VERSION 5.7 ;
  DIVIDERCHAR "/" ;
  BUSBITCHARS "[]" ;
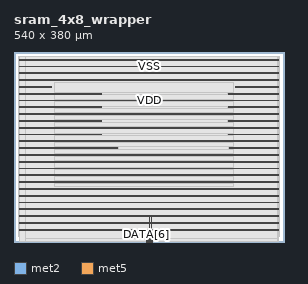
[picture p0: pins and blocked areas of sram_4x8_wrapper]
MACRO sram_4x8_wrapper
  CLASS BLOCK ;
  FOREIGN sram_4x8_wrapper ;
  ORIGIN 0.000 0.000 ;
  SIZE 540.000 BY 380.000 ;
  PIN ADDR[0]
    ANTENNAGATEAREA 0.126000 ;
    DIRECTION INPUT ;
    USE SIGNAL ;
    PORT
      LAYER met2 ;
        RECT 276.160 0.000 276.300 17.040 ;
    END
  END ADDR[0]
  PIN ADDR[1]
    ANTENNAGATEAREA 0.126000 ;
    DIRECTION INPUT ;
    USE SIGNAL ;
    PORT
      LAYER met2 ;
        RECT 269.720 0.000 269.860 16.700 ;
    END
  END ADDR[1]
  PIN CLK
    ANTENNAGATEAREA 0.213000 ;
    DIRECTION INPUT ;
    USE CLOCK ;
    PORT
      LAYER met2 ;
        RECT 273.400 0.000 273.540 6.320 ;
    END
  END CLK
  PIN CSb
    ANTENNAGATEAREA 0.495000 ;
    DIRECTION INPUT ;
    USE SIGNAL ;
    PORT
      LAYER met2 ;
        RECT 270.640 0.000 270.780 9.250 ;
    END
  END CSb
  PIN DATA[0]
    ANTENNAGATEAREA 0.126000 ;
    ANTENNADIFFAREA 0.601000 ;
    DIRECTION INOUT ;
    USE SIGNAL ;
    PORT
      LAYER met2 ;
        RECT 267.880 0.000 268.020 10.240 ;
    END
  END DATA[0]
  PIN DATA[1]
    ANTENNAGATEAREA 0.126000 ;
    ANTENNADIFFAREA 0.601000 ;
    DIRECTION INOUT ;
    USE SIGNAL ;
    PORT
      LAYER met2 ;
        RECT 266.960 0.000 267.100 9.930 ;
    END
  END DATA[1]
  PIN DATA[2]
    ANTENNAGATEAREA 0.126000 ;
    ANTENNADIFFAREA 0.601000 ;
    DIRECTION INOUT ;
    USE SIGNAL ;
    PORT
      LAYER met2 ;
        RECT 275.240 0.000 275.380 53.760 ;
    END
  END DATA[2]
  PIN DATA[3]
    ANTENNAGATEAREA 0.126000 ;
    ANTENNADIFFAREA 0.601000 ;
    DIRECTION INOUT ;
    USE SIGNAL ;
    PORT
      LAYER met2 ;
        RECT 271.560 0.000 271.700 51.040 ;
    END
  END DATA[3]
  PIN DATA[4]
    ANTENNAGATEAREA 0.126000 ;
    ANTENNADIFFAREA 0.601000 ;
    DIRECTION INOUT ;
    USE SIGNAL ;
    PORT
      LAYER met2 ;
        RECT 265.120 0.000 265.260 17.410 ;
    END
  END DATA[4]
  PIN DATA[5]
    ANTENNAGATEAREA 0.126000 ;
    ANTENNADIFFAREA 0.601000 ;
    DIRECTION INOUT ;
    USE SIGNAL ;
    PORT
      LAYER met2 ;
        RECT 274.320 0.000 274.460 1.060 ;
    END
  END DATA[5]
  PIN DATA[6]
    ANTENNAGATEAREA 0.126000 ;
    ANTENNADIFFAREA 0.601000 ;
    DIRECTION INOUT ;
    USE SIGNAL ;
    PORT
      LAYER met2 ;
        RECT 264.200 0.000 264.340 0.485 ;
    END
  END DATA[6]
  PIN DATA[7]
    ANTENNAGATEAREA 0.126000 ;
    ANTENNADIFFAREA 0.601000 ;
    DIRECTION INOUT ;
    USE SIGNAL ;
    PORT
      LAYER met2 ;
        RECT 272.480 0.000 272.620 0.720 ;
    END
  END DATA[7]
  PIN OEb
    ANTENNAGATEAREA 0.373500 ;
    DIRECTION INPUT ;
    USE SIGNAL ;
    PORT
      LAYER met2 ;
        RECT 266.040 0.000 266.180 11.600 ;
    END
  END OEb
  PIN VDD
    ANTENNADIFFAREA 655.891357 ;
    DIRECTION INOUT ;
    USE POWER ;
    PORT
      LAYER met5 ;
        RECT 443.560 309.280 529.920 310.880 ;
    END
    PORT
      LAYER met5 ;
        RECT 10.120 363.680 529.920 365.280 ;
    END
    PORT
      LAYER met5 ;
        RECT 10.120 336.480 529.920 338.080 ;
    END
    PORT
      LAYER met5 ;
        RECT 10.120 309.280 74.800 310.880 ;
    END
    PORT
      LAYER met5 ;
        RECT 10.120 282.080 529.920 283.680 ;
    END
    PORT
      LAYER met5 ;
        RECT 10.120 254.880 529.920 256.480 ;
    END
    PORT
      LAYER met5 ;
        RECT 10.120 227.680 529.920 229.280 ;
    END
    PORT
      LAYER met5 ;
        RECT 10.120 200.480 529.920 202.080 ;
    END
    PORT
      LAYER met5 ;
        RECT 10.120 173.280 529.920 174.880 ;
    END
    PORT
      LAYER met5 ;
        RECT 10.120 146.080 529.920 147.680 ;
    END
    PORT
      LAYER met5 ;
        RECT 10.120 118.880 529.920 120.480 ;
    END
    PORT
      LAYER met5 ;
        RECT 10.120 91.680 529.920 93.280 ;
    END
    PORT
      LAYER met5 ;
        RECT 10.120 64.480 529.920 66.080 ;
    END
    PORT
      LAYER met5 ;
        RECT 10.120 37.280 529.920 38.880 ;
    END
  END VDD
  PIN VSS
    ANTENNADIFFAREA 590.426941 ;
    DIRECTION INOUT ;
    USE GROUND ;
    PORT
      LAYER met5 ;
        RECT 431.100 186.880 529.920 188.480 ;
    END
    PORT
      LAYER met5 ;
        RECT 429.500 295.680 529.920 297.280 ;
    END
    PORT
      LAYER met5 ;
        RECT 429.500 268.480 529.920 270.080 ;
    END
    PORT
      LAYER met5 ;
        RECT 429.500 241.280 529.920 242.880 ;
    END
    PORT
      LAYER met5 ;
        RECT 429.500 214.080 529.920 215.680 ;
    END
    PORT
      LAYER met5 ;
        RECT 10.120 350.080 529.920 351.680 ;
    END
    PORT
      LAYER met5 ;
        RECT 10.120 322.880 529.920 324.480 ;
    END
    PORT
      LAYER met5 ;
        RECT 10.120 295.680 174.350 297.280 ;
    END
    PORT
      LAYER met5 ;
        RECT 10.120 268.480 174.350 270.080 ;
    END
    PORT
      LAYER met5 ;
        RECT 10.120 241.280 174.350 242.880 ;
    END
    PORT
      LAYER met5 ;
        RECT 10.120 214.080 174.350 215.680 ;
    END
    PORT
      LAYER met5 ;
        RECT 10.120 186.880 207.750 188.480 ;
    END
    PORT
      LAYER met5 ;
        RECT 10.120 159.680 529.920 161.280 ;
    END
    PORT
      LAYER met5 ;
        RECT 10.120 132.480 529.920 134.080 ;
    END
    PORT
      LAYER met5 ;
        RECT 10.120 105.280 529.920 106.880 ;
    END
    PORT
      LAYER met5 ;
        RECT 10.120 78.080 529.920 79.680 ;
    END
    PORT
      LAYER met5 ;
        RECT 10.120 50.880 529.920 52.480 ;
    END
    PORT
      LAYER met5 ;
        RECT 10.120 23.680 529.920 25.280 ;
    END
  END VSS
  PIN WEb
    ANTENNAGATEAREA 0.373500 ;
    DIRECTION INPUT ;
    USE SIGNAL ;
    PORT
      LAYER met2 ;
        RECT 268.800 0.000 268.940 9.930 ;
    END
  END WEb
  OBS
      LAYER nwell ;
        RECT 9.930 10.760 530.110 370.040 ;
      LAYER li1 ;
        RECT 10.120 10.795 529.920 370.005 ;
      LAYER met1 ;
        RECT 10.120 0.380 529.920 370.160 ;
      LAYER met2 ;
        RECT 22.920 54.040 526.550 370.105 ;
        RECT 22.920 51.320 274.960 54.040 ;
        RECT 22.920 17.690 271.280 51.320 ;
        RECT 22.920 0.765 264.840 17.690 ;
        RECT 22.920 0.350 263.920 0.765 ;
        RECT 264.620 0.350 264.840 0.765 ;
        RECT 265.540 16.980 271.280 17.690 ;
        RECT 265.540 11.880 269.440 16.980 ;
        RECT 265.540 0.350 265.760 11.880 ;
        RECT 266.460 10.520 269.440 11.880 ;
        RECT 266.460 10.210 267.600 10.520 ;
        RECT 266.460 0.350 266.680 10.210 ;
        RECT 267.380 0.350 267.600 10.210 ;
        RECT 268.300 10.210 269.440 10.520 ;
        RECT 268.300 0.350 268.520 10.210 ;
        RECT 269.220 0.350 269.440 10.210 ;
        RECT 270.140 9.530 271.280 16.980 ;
        RECT 270.140 0.350 270.360 9.530 ;
        RECT 271.060 0.350 271.280 9.530 ;
        RECT 271.980 6.600 274.960 51.320 ;
        RECT 271.980 1.000 273.120 6.600 ;
        RECT 271.980 0.350 272.200 1.000 ;
        RECT 272.900 0.350 273.120 1.000 ;
        RECT 273.820 1.340 274.960 6.600 ;
        RECT 273.820 0.350 274.040 1.340 ;
        RECT 274.740 0.350 274.960 1.340 ;
        RECT 275.660 17.320 526.550 54.040 ;
        RECT 275.660 0.350 275.880 17.320 ;
        RECT 276.580 0.350 526.550 17.320 ;
      LAYER met3 ;
        RECT 22.900 6.295 526.570 370.085 ;
      LAYER met4 ;
        RECT 22.890 6.295 526.580 370.160 ;
      LAYER met5 ;
        RECT 80.000 298.880 439.000 318.500 ;
        RECT 175.950 294.080 427.900 298.880 ;
        RECT 80.000 285.280 439.000 294.080 ;
        RECT 80.000 271.680 439.000 280.480 ;
        RECT 175.950 266.880 427.900 271.680 ;
        RECT 80.000 258.080 439.000 266.880 ;
        RECT 80.000 244.480 439.000 253.280 ;
        RECT 175.950 239.680 427.900 244.480 ;
        RECT 80.000 230.880 439.000 239.680 ;
        RECT 80.000 217.280 439.000 226.080 ;
        RECT 175.950 212.480 427.900 217.280 ;
        RECT 80.000 203.680 439.000 212.480 ;
        RECT 80.000 190.080 439.000 198.880 ;
        RECT 209.350 185.280 429.500 190.080 ;
        RECT 80.000 176.480 439.000 185.280 ;
        RECT 80.000 162.880 439.000 171.680 ;
        RECT 80.000 149.280 439.000 158.080 ;
        RECT 80.000 135.680 439.000 144.480 ;
        RECT 80.000 122.080 439.000 130.880 ;
        RECT 80.000 111.500 439.000 117.280 ;
  END
END sram_4x8_wrapper
END LIBRARY

